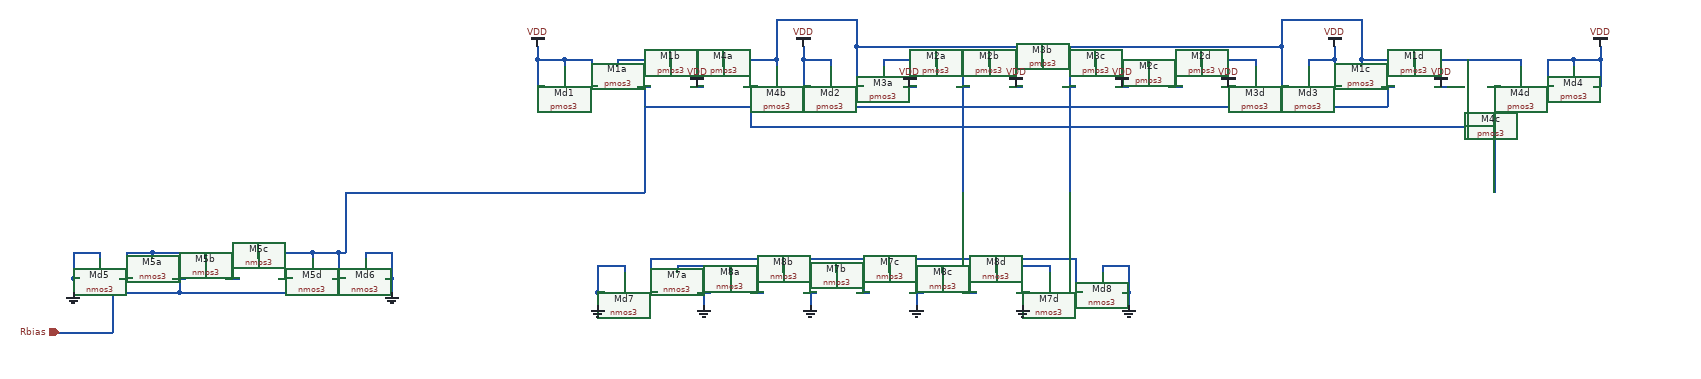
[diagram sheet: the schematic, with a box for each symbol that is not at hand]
v {xschem version=2.9.9 file_version=1.2 }
G {}
K {}
V {}
S {}
E {}
N 860 -950 880 -950 { lab=VDD}
N 940 -950 960 -950 { lab=#net1}
N 1020 -950 1040 -950 { lab=VDD}
N 1100 -950 1120 -950 { lab=#net2}
N 1180 -950 1200 -950 { lab=VDD}
N 1260 -950 1280 -950 { lab=#net3}
N 1340 -950 1360 -950 { lab=VDD}
N 1420 -950 1440 -950 { lab=#net4}
N 1500 -950 1520 -950 { lab=VDD}
N 1580 -950 1600 -950 { lab=#net3}
N 1660 -950 1680 -950 { lab=VDD}
N 1740 -950 1760 -950 { lab=#net4}
N 1820 -950 1840 -950 { lab=VDD}
N 1900 -950 1920 -950 { lab=#net3}
N 1980 -950 2000 -950 { lab=VDD}
N 2060 -950 2080 -950 { lab=#net1}
N 2140 -950 2160 -950 { lab=VDD}
N 2220 -950 2240 -950 { lab=#net2}
N 2300 -950 2320 -950 { lab=VDD}
N 790 -950 800 -950 { lab=VDD}
N 790 -990 790 -950 { lab=VDD}
N 790 -990 830 -990 { lab=VDD}
N 830 -990 830 -980 { lab=VDD}
N 790 -1010 790 -990 { lab=VDD}
N 2380 -950 2390 -950 { lab=VDD}
N 2350 -990 2350 -980 { lab=VDD}
N 2350 -990 2390 -990 { lab=VDD}
N 2390 -990 2390 -950 { lab=VDD}
N 2390 -1010 2390 -990 { lab=VDD}
N 1310 -990 1310 -980 { lab=#net4}
N 1310 -990 1870 -990 { lab=#net4}
N 1870 -990 1870 -980 { lab=#net4}
N 1790 -990 1790 -980 { lab=#net4}
N 1710 -990 1710 -980 { lab=#net4}
N 1630 -990 1630 -980 { lab=#net4}
N 1550 -990 1550 -980 { lab=#net4}
N 1470 -990 1470 -980 { lab=#net4}
N 1390 -990 1390 -980 { lab=#net4}
N 1430 -990 1430 -950 { lab=#net4}
N 1750 -990 1750 -950 { lab=#net4}
N 1910 -1010 1910 -950 { lab=#net3}
N 1270 -1010 1910 -1010 { lab=#net3}
N 1270 -1010 1270 -950 { lab=#net3}
N 1590 -1010 1590 -950 { lab=#net3}
N 1590 -950 1590 -790 { lab=#net3}
N 1430 -950 1430 -790 { lab=#net4}
N 1950 -990 1950 -980 { lab=VDD}
N 1950 -990 1990 -990 { lab=VDD}
N 1990 -990 1990 -950 { lab=VDD}
N 1990 -1010 1990 -990 { lab=VDD}
N 2270 -990 2270 -980 { lab=#net3}
N 2190 -990 2190 -980 { lab=#net3}
N 2110 -990 2110 -980 { lab=#net3}
N 2030 -990 2030 -980 { lab=#net3}
N 2030 -990 2270 -990 { lab=#net3}
N 1230 -990 1230 -980 { lab=VDD}
N 1190 -990 1230 -990 { lab=VDD}
N 1190 -990 1190 -950 { lab=VDD}
N 1190 -1010 1190 -990 { lab=VDD}
N 910 -990 910 -980 { lab=#net3}
N 910 -990 1150 -990 { lab=#net3}
N 1150 -990 1150 -980 { lab=#net3}
N 1070 -990 1070 -980 { lab=#net3}
N 990 -990 990 -980 { lab=#net3}
N 1150 -1050 1150 -990 { lab=#net3}
N 1150 -1050 1270 -1050 { lab=#net3}
N 1270 -1050 1270 -1010 { lab=#net3}
N 2030 -1050 2030 -990 { lab=#net3}
N 1910 -1050 2030 -1050 { lab=#net3}
N 1910 -1050 1910 -1010 { lab=#net3}
N 2230 -950 2230 -840 { lab=#net2}
N 2310 -990 2310 -950 { lab=VDD}
N 2310 -990 2350 -990 { lab=VDD}
N 870 -990 870 -950 { lab=VDD}
N 830 -990 870 -990 { lab=VDD}
N 950 -950 950 -790 { lab=#net1}
N 2230 -840 2230 -790 { lab=#net2}
N 2070 -950 2070 -920 { lab=#net1}
N 950 -920 2070 -920 { lab=#net1}
N 1110 -950 1110 -890 { lab=#net2}
N 1110 -890 2230 -890 { lab=#net2}
N 400 -660 420 -660 { lab=Rbias}
N 320 -660 340 -660 { lab=#net1}
N 240 -660 260 -660 { lab=Rbias}
N 450 -700 450 -690 { lab=#net1}
N 210 -700 450 -700 { lab=#net1}
N 210 -700 210 -690 { lab=#net1}
N 290 -700 290 -690 { lab=#net1}
N 370 -700 370 -690 { lab=#net1}
N 410 -660 410 -640 { lab=Rbias}
N 250 -640 410 -640 { lab=Rbias}
N 250 -660 250 -640 { lab=Rbias}
N 150 -640 250 -640 { lab=Rbias}
N 170 -660 180 -660 { lab=#net1}
N 480 -660 490 -660 { lab=#net1}
N 170 -700 210 -700 { lab=#net1}
N 170 -700 170 -660 { lab=#net1}
N 450 -700 490 -700 { lab=#net1}
N 490 -700 490 -660 { lab=#net1}
N 330 -700 330 -660 { lab=#net1}
N 500 -790 950 -790 { lab=#net1}
N 500 -790 500 -700 { lab=#net1}
N 490 -700 500 -700 { lab=#net1}
N 490 -660 500 -660 { lab=#net1}
N 530 -700 530 -690 { lab=GND}
N 530 -700 570 -700 { lab=GND}
N 570 -700 570 -660 { lab=GND}
N 560 -660 570 -660 { lab=GND}
N 570 -660 570 -640 { lab=GND}
N 160 -660 170 -660 { lab=#net1}
N 130 -700 130 -690 { lab=GND}
N 100 -700 130 -700 { lab=GND}
N 90 -660 100 -660 { lab=GND}
N 90 -700 100 -700 { lab=GND}
N 90 -700 90 -660 { lab=GND}
N 90 -660 90 -640 { lab=GND}
N 150 -640 150 -580 { lab=Rbias}
N 70 -580 150 -580 { lab=Rbias}
N 920 -680 920 -670 { lab=GND}
N 1000 -680 1000 -670 { lab=#net5}
N 1080 -680 1080 -670 { lab=#net5}
N 1160 -680 1160 -670 { lab=#net5}
N 950 -640 970 -640 { lab=#net5}
N 1030 -640 1050 -640 { lab=GND}
N 1110 -640 1130 -640 { lab=#net6}
N 1190 -640 1210 -640 { lab=#net7}
N 1240 -680 1240 -670 { lab=#net5}
N 1320 -680 1320 -670 { lab=#net5}
N 1400 -680 1400 -670 { lab=#net5}
N 1480 -680 1480 -670 { lab=#net5}
N 1270 -640 1290 -640 { lab=#net5}
N 1350 -640 1370 -640 { lab=#net8}
N 1430 -640 1450 -640 { lab=#net9}
N 1510 -640 1530 -640 { lab=#net10}
N 1560 -680 1560 -670 { lab=#net5}
N 1640 -680 1640 -670 { lab=GND}
N 1590 -640 1610 -640 { lab=#net5}
N 1000 -680 1560 -680 { lab=#net5}
N 880 -680 920 -680 { lab=GND}
N 880 -680 880 -640 { lab=GND}
N 880 -640 890 -640 { lab=GND}
N 1670 -640 1680 -640 { lab=GND}
N 1680 -680 1680 -640 { lab=GND}
N 1640 -680 1680 -680 { lab=GND}
N 1680 -640 1680 -620 { lab=GND}
N 880 -640 880 -620 { lab=GND}
N 1040 -640 1040 -620 { lab=GND}
N 1200 -640 1200 -620 { lab=GND}
N 1360 -640 1360 -620 { lab=GND}
N 1520 -640 1520 -620 { lab=GND}
N 1120 -680 1120 -640 {}
N 1440 -680 1440 -640 {}
N 960 -690 960 -640 {}
N 960 -690 1600 -690 {}
N 1600 -690 1600 -640 {}
N 1280 -690 1280 -640 {}
C {madvlsi/pmos3.sym} 830 -950 1 0 {name=Md1
L=0.5
W=1.4/4
body=VDD
nf=1
mult=1
ad="'int((nf+1)/2) * W/nf * 0.29'" 
pd="'2*int((nf+1)/2) * (W/nf + 0.29)'"
as="'int((nf+2)/2) * W/nf * 0.29'" 
ps="'2*int((nf+2)/2) * (W/nf + 0.29)'"
nrd="'0.29 / W'" nrs="'0.29 / W'"
sa=0 sb=0 sd=0
model=pfet_01v8
spiceprefix=X
}
C {madvlsi/pmos3.sym} 910 -950 1 0 {name=M1a
L=0.5
W=1.4/4
body=VDD
nf=1
mult=1
ad="'int((nf+1)/2) * W/nf * 0.29'" 
pd="'2*int((nf+1)/2) * (W/nf + 0.29)'"
as="'int((nf+2)/2) * W/nf * 0.29'" 
ps="'2*int((nf+2)/2) * (W/nf + 0.29)'"
nrd="'0.29 / W'" nrs="'0.29 / W'"
sa=0 sb=0 sd=0
model=pfet_01v8
spiceprefix=X
}
C {madvlsi/pmos3.sym} 990 -950 1 0 {name=M1b
L=0.5
W=1.4/4
body=VDD
nf=1
mult=1
ad="'int((nf+1)/2) * W/nf * 0.29'" 
pd="'2*int((nf+1)/2) * (W/nf + 0.29)'"
as="'int((nf+2)/2) * W/nf * 0.29'" 
ps="'2*int((nf+2)/2) * (W/nf + 0.29)'"
nrd="'0.29 / W'" nrs="'0.29 / W'"
sa=0 sb=0 sd=0
model=pfet_01v8
spiceprefix=X
}
C {madvlsi/pmos3.sym} 1070 -950 1 0 {name=M4a
L=0.5
W=1.4/4
body=VDD
nf=1
mult=1
ad="'int((nf+1)/2) * W/nf * 0.29'" 
pd="'2*int((nf+1)/2) * (W/nf + 0.29)'"
as="'int((nf+2)/2) * W/nf * 0.29'" 
ps="'2*int((nf+2)/2) * (W/nf + 0.29)'"
nrd="'0.29 / W'" nrs="'0.29 / W'"
sa=0 sb=0 sd=0
model=pfet_01v8
spiceprefix=X
}
C {madvlsi/pmos3.sym} 1150 -950 1 0 {name=M4b
L=0.5
W=1.4/4
body=VDD
nf=1
mult=1
ad="'int((nf+1)/2) * W/nf * 0.29'" 
pd="'2*int((nf+1)/2) * (W/nf + 0.29)'"
as="'int((nf+2)/2) * W/nf * 0.29'" 
ps="'2*int((nf+2)/2) * (W/nf + 0.29)'"
nrd="'0.29 / W'" nrs="'0.29 / W'"
sa=0 sb=0 sd=0
model=pfet_01v8
spiceprefix=X
}
C {madvlsi/pmos3.sym} 1230 -950 1 0 {name=Md2
L=0.5
W=1.4/4
body=VDD
nf=1
mult=1
ad="'int((nf+1)/2) * W/nf * 0.29'" 
pd="'2*int((nf+1)/2) * (W/nf + 0.29)'"
as="'int((nf+2)/2) * W/nf * 0.29'" 
ps="'2*int((nf+2)/2) * (W/nf + 0.29)'"
nrd="'0.29 / W'" nrs="'0.29 / W'"
sa=0 sb=0 sd=0
model=pfet_01v8
spiceprefix=X
}
C {madvlsi/pmos3.sym} 1310 -950 1 0 {name=M3a
L=0.5
W=1.4/4
body=VDD
nf=1
mult=1
ad="'int((nf+1)/2) * W/nf * 0.29'" 
pd="'2*int((nf+1)/2) * (W/nf + 0.29)'"
as="'int((nf+2)/2) * W/nf * 0.29'" 
ps="'2*int((nf+2)/2) * (W/nf + 0.29)'"
nrd="'0.29 / W'" nrs="'0.29 / W'"
sa=0 sb=0 sd=0
model=pfet_01v8
spiceprefix=X
}
C {madvlsi/pmos3.sym} 1390 -950 1 0 {name=M2a
L=0.5
W=1.4/4
body=VDD
nf=1
mult=1
ad="'int((nf+1)/2) * W/nf * 0.29'" 
pd="'2*int((nf+1)/2) * (W/nf + 0.29)'"
as="'int((nf+2)/2) * W/nf * 0.29'" 
ps="'2*int((nf+2)/2) * (W/nf + 0.29)'"
nrd="'0.29 / W'" nrs="'0.29 / W'"
sa=0 sb=0 sd=0
model=pfet_01v8
spiceprefix=X
}
C {madvlsi/pmos3.sym} 1470 -950 1 0 {name=M2b
L=0.5
W=1.4/4
body=VDD
nf=1
mult=1
ad="'int((nf+1)/2) * W/nf * 0.29'" 
pd="'2*int((nf+1)/2) * (W/nf + 0.29)'"
as="'int((nf+2)/2) * W/nf * 0.29'" 
ps="'2*int((nf+2)/2) * (W/nf + 0.29)'"
nrd="'0.29 / W'" nrs="'0.29 / W'"
sa=0 sb=0 sd=0
model=pfet_01v8
spiceprefix=X
}
C {madvlsi/pmos3.sym} 1550 -950 1 0 {name=M3b
L=0.5
W=1.4/4
body=VDD
nf=1
mult=1
ad="'int((nf+1)/2) * W/nf * 0.29'" 
pd="'2*int((nf+1)/2) * (W/nf + 0.29)'"
as="'int((nf+2)/2) * W/nf * 0.29'" 
ps="'2*int((nf+2)/2) * (W/nf + 0.29)'"
nrd="'0.29 / W'" nrs="'0.29 / W'"
sa=0 sb=0 sd=0
model=pfet_01v8
spiceprefix=X
}
C {madvlsi/pmos3.sym} 1630 -950 1 0 {name=M3c
L=0.5
W=1.4/4
body=VDD
nf=1
mult=1
ad="'int((nf+1)/2) * W/nf * 0.29'" 
pd="'2*int((nf+1)/2) * (W/nf + 0.29)'"
as="'int((nf+2)/2) * W/nf * 0.29'" 
ps="'2*int((nf+2)/2) * (W/nf + 0.29)'"
nrd="'0.29 / W'" nrs="'0.29 / W'"
sa=0 sb=0 sd=0
model=pfet_01v8
spiceprefix=X
}
C {madvlsi/pmos3.sym} 1710 -950 1 0 {name=M2c
L=0.5
W=1.4/4
body=VDD
nf=1
mult=1
ad="'int((nf+1)/2) * W/nf * 0.29'" 
pd="'2*int((nf+1)/2) * (W/nf + 0.29)'"
as="'int((nf+2)/2) * W/nf * 0.29'" 
ps="'2*int((nf+2)/2) * (W/nf + 0.29)'"
nrd="'0.29 / W'" nrs="'0.29 / W'"
sa=0 sb=0 sd=0
model=pfet_01v8
spiceprefix=X
}
C {madvlsi/pmos3.sym} 1790 -950 1 0 {name=M2d
L=0.5
W=1.4/4
body=VDD
nf=1
mult=1
ad="'int((nf+1)/2) * W/nf * 0.29'" 
pd="'2*int((nf+1)/2) * (W/nf + 0.29)'"
as="'int((nf+2)/2) * W/nf * 0.29'" 
ps="'2*int((nf+2)/2) * (W/nf + 0.29)'"
nrd="'0.29 / W'" nrs="'0.29 / W'"
sa=0 sb=0 sd=0
model=pfet_01v8
spiceprefix=X
}
C {madvlsi/pmos3.sym} 1870 -950 1 0 {name=M3d
L=0.5
W=1.4/4
body=VDD
nf=1
mult=1
ad="'int((nf+1)/2) * W/nf * 0.29'" 
pd="'2*int((nf+1)/2) * (W/nf + 0.29)'"
as="'int((nf+2)/2) * W/nf * 0.29'" 
ps="'2*int((nf+2)/2) * (W/nf + 0.29)'"
nrd="'0.29 / W'" nrs="'0.29 / W'"
sa=0 sb=0 sd=0
model=pfet_01v8
spiceprefix=X
}
C {madvlsi/pmos3.sym} 1950 -950 1 0 {name=Md3
L=0.5
W=1.4/4
body=VDD
nf=1
mult=1
ad="'int((nf+1)/2) * W/nf * 0.29'" 
pd="'2*int((nf+1)/2) * (W/nf + 0.29)'"
as="'int((nf+2)/2) * W/nf * 0.29'" 
ps="'2*int((nf+2)/2) * (W/nf + 0.29)'"
nrd="'0.29 / W'" nrs="'0.29 / W'"
sa=0 sb=0 sd=0
model=pfet_01v8
spiceprefix=X
}
C {madvlsi/pmos3.sym} 2030 -950 1 0 {name=M1c
L=0.5
W=1.4/4
body=VDD
nf=1
mult=1
ad="'int((nf+1)/2) * W/nf * 0.29'" 
pd="'2*int((nf+1)/2) * (W/nf + 0.29)'"
as="'int((nf+2)/2) * W/nf * 0.29'" 
ps="'2*int((nf+2)/2) * (W/nf + 0.29)'"
nrd="'0.29 / W'" nrs="'0.29 / W'"
sa=0 sb=0 sd=0
model=pfet_01v8
spiceprefix=X
}
C {madvlsi/pmos3.sym} 2110 -950 1 0 {name=M1d
L=0.5
W=1.4/4
body=VDD
nf=1
mult=1
ad="'int((nf+1)/2) * W/nf * 0.29'" 
pd="'2*int((nf+1)/2) * (W/nf + 0.29)'"
as="'int((nf+2)/2) * W/nf * 0.29'" 
ps="'2*int((nf+2)/2) * (W/nf + 0.29)'"
nrd="'0.29 / W'" nrs="'0.29 / W'"
sa=0 sb=0 sd=0
model=pfet_01v8
spiceprefix=X
}
C {madvlsi/pmos3.sym} 2190 -950 1 0 {name=M4c
L=0.5
W=1.4/4
body=VDD
nf=1
mult=1
ad="'int((nf+1)/2) * W/nf * 0.29'" 
pd="'2*int((nf+1)/2) * (W/nf + 0.29)'"
as="'int((nf+2)/2) * W/nf * 0.29'" 
ps="'2*int((nf+2)/2) * (W/nf + 0.29)'"
nrd="'0.29 / W'" nrs="'0.29 / W'"
sa=0 sb=0 sd=0
model=pfet_01v8
spiceprefix=X
}
C {madvlsi/pmos3.sym} 2270 -950 1 0 {name=M4d
L=0.5
W=1.4/4
body=VDD
nf=1
mult=1
ad="'int((nf+1)/2) * W/nf * 0.29'" 
pd="'2*int((nf+1)/2) * (W/nf + 0.29)'"
as="'int((nf+2)/2) * W/nf * 0.29'" 
ps="'2*int((nf+2)/2) * (W/nf + 0.29)'"
nrd="'0.29 / W'" nrs="'0.29 / W'"
sa=0 sb=0 sd=0
model=pfet_01v8
spiceprefix=X
}
C {madvlsi/pmos3.sym} 2350 -950 1 0 {name=Md4
L=0.5
W=1.4/4
body=VDD
nf=1
mult=1
ad="'int((nf+1)/2) * W/nf * 0.29'" 
pd="'2*int((nf+1)/2) * (W/nf + 0.29)'"
as="'int((nf+2)/2) * W/nf * 0.29'" 
ps="'2*int((nf+2)/2) * (W/nf + 0.29)'"
nrd="'0.29 / W'" nrs="'0.29 / W'"
sa=0 sb=0 sd=0
model=pfet_01v8
spiceprefix=X
}
C {madvlsi/vdd.sym} 1350 -950 0 0 {name=l1 lab=VDD}
C {madvlsi/vdd.sym} 1510 -950 0 0 {name=l2 lab=VDD}
C {madvlsi/vdd.sym} 1670 -950 0 0 {name=l3 lab=VDD}
C {madvlsi/vdd.sym} 1830 -950 0 0 {name=l4 lab=VDD}
C {madvlsi/vdd.sym} 1990 -1010 0 0 {name=l5 lab=VDD}
C {madvlsi/vdd.sym} 2390 -1010 0 0 {name=l6 lab=VDD}
C {madvlsi/vdd.sym} 1190 -1010 0 0 {name=l7 lab=VDD}
C {madvlsi/vdd.sym} 790 -1010 0 0 {name=l8 lab=VDD}
C {madvlsi/vdd.sym} 1030 -950 0 0 {name=l9 lab=VDD}
C {madvlsi/vdd.sym} 2150 -950 0 0 {name=l10 lab=VDD}
C {madvlsi/nmos3.sym} 210 -660 1 0 {name=M5a
L=0.5
W=1.4*2
body=GND
nf=1
mult=1
ad="'int((nf+1)/2) * W/nf * 0.29'" 
pd="'2*int((nf+1)/2) * (W/nf + 0.29)'"
as="'int((nf+2)/2) * W/nf * 0.29'" 
ps="'2*int((nf+2)/2) * (W/nf + 0.29)'"
nrd="'0.29 / W'" nrs="'0.29 / W'"
sa=0 sb=0 sd=0
model=nfet_01v8
spiceprefix=X
}
C {madvlsi/nmos3.sym} 290 -660 1 0 {name=M5b
L=0.5
W=1.4*2
body=GND
nf=1
mult=1
ad="'int((nf+1)/2) * W/nf * 0.29'" 
pd="'2*int((nf+1)/2) * (W/nf + 0.29)'"
as="'int((nf+2)/2) * W/nf * 0.29'" 
ps="'2*int((nf+2)/2) * (W/nf + 0.29)'"
nrd="'0.29 / W'" nrs="'0.29 / W'"
sa=0 sb=0 sd=0
model=nfet_01v8
spiceprefix=X
}
C {madvlsi/nmos3.sym} 370 -660 1 0 {name=M5c
L=0.5
W=1.4*2
body=GND
nf=1
mult=1
ad="'int((nf+1)/2) * W/nf * 0.29'" 
pd="'2*int((nf+1)/2) * (W/nf + 0.29)'"
as="'int((nf+2)/2) * W/nf * 0.29'" 
ps="'2*int((nf+2)/2) * (W/nf + 0.29)'"
nrd="'0.29 / W'" nrs="'0.29 / W'"
sa=0 sb=0 sd=0
model=nfet_01v8
spiceprefix=X
}
C {madvlsi/nmos3.sym} 450 -660 1 0 {name=M5d
L=0.5
W=1.4*2
body=GND
nf=1
mult=1
ad="'int((nf+1)/2) * W/nf * 0.29'" 
pd="'2*int((nf+1)/2) * (W/nf + 0.29)'"
as="'int((nf+2)/2) * W/nf * 0.29'" 
ps="'2*int((nf+2)/2) * (W/nf + 0.29)'"
nrd="'0.29 / W'" nrs="'0.29 / W'"
sa=0 sb=0 sd=0
model=nfet_01v8
spiceprefix=X
}
C {madvlsi/nmos3.sym} 530 -660 1 0 {name=Md6
L=0.5
W=1.4*2
body=GND
nf=1
mult=1
ad="'int((nf+1)/2) * W/nf * 0.29'" 
pd="'2*int((nf+1)/2) * (W/nf + 0.29)'"
as="'int((nf+2)/2) * W/nf * 0.29'" 
ps="'2*int((nf+2)/2) * (W/nf + 0.29)'"
nrd="'0.29 / W'" nrs="'0.29 / W'"
sa=0 sb=0 sd=0
model=nfet_01v8
spiceprefix=X
}
C {madvlsi/nmos3.sym} 130 -660 1 0 {name=Md5
L=0.5
W=1.4*2
body=GND
nf=1
mult=1
ad="'int((nf+1)/2) * W/nf * 0.29'" 
pd="'2*int((nf+1)/2) * (W/nf + 0.29)'"
as="'int((nf+2)/2) * W/nf * 0.29'" 
ps="'2*int((nf+2)/2) * (W/nf + 0.29)'"
nrd="'0.29 / W'" nrs="'0.29 / W'"
sa=0 sb=0 sd=0
model=nfet_01v8
spiceprefix=X
}
C {madvlsi/gnd.sym} 90 -640 0 0 {name=l11 lab=GND}
C {madvlsi/gnd.sym} 570 -640 0 0 {name=l12 lab=GND}
C {devices/iopin.sym} 70 -580 2 0 {name=p1 lab=Rbias}
C {madvlsi/nmos3.sym} 920 -640 1 0 {name=Md7
L=0.5
W=1.4/4
body=GND
nf=1
mult=1
ad="'int((nf+1)/2) * W/nf * 0.29'" 
pd="'2*int((nf+1)/2) * (W/nf + 0.29)'"
as="'int((nf+2)/2) * W/nf * 0.29'" 
ps="'2*int((nf+2)/2) * (W/nf + 0.29)'"
nrd="'0.29 / W'" nrs="'0.29 / W'"
sa=0 sb=0 sd=0
model=nfet_01v8
spiceprefix=X
}
C {madvlsi/nmos3.sym} 1000 -640 1 0 {name=M7a
L=0.5
W=1.4/4
body=GND
nf=1
mult=1
ad="'int((nf+1)/2) * W/nf * 0.29'" 
pd="'2*int((nf+1)/2) * (W/nf + 0.29)'"
as="'int((nf+2)/2) * W/nf * 0.29'" 
ps="'2*int((nf+2)/2) * (W/nf + 0.29)'"
nrd="'0.29 / W'" nrs="'0.29 / W'"
sa=0 sb=0 sd=0
model=nfet_01v8
spiceprefix=X
}
C {madvlsi/nmos3.sym} 1080 -640 1 0 {name=M8a
L=0.5
W=1.4/4
body=GND
nf=1
mult=1
ad="'int((nf+1)/2) * W/nf * 0.29'" 
pd="'2*int((nf+1)/2) * (W/nf + 0.29)'"
as="'int((nf+2)/2) * W/nf * 0.29'" 
ps="'2*int((nf+2)/2) * (W/nf + 0.29)'"
nrd="'0.29 / W'" nrs="'0.29 / W'"
sa=0 sb=0 sd=0
model=nfet_01v8
spiceprefix=X
}
C {madvlsi/nmos3.sym} 1160 -640 1 0 {name=M8b
L=0.5
W=1.4/4
body=GND
nf=1
mult=1
ad="'int((nf+1)/2) * W/nf * 0.29'" 
pd="'2*int((nf+1)/2) * (W/nf + 0.29)'"
as="'int((nf+2)/2) * W/nf * 0.29'" 
ps="'2*int((nf+2)/2) * (W/nf + 0.29)'"
nrd="'0.29 / W'" nrs="'0.29 / W'"
sa=0 sb=0 sd=0
model=nfet_01v8
spiceprefix=X
}
C {madvlsi/nmos3.sym} 1240 -640 1 0 {name=M7b
L=0.5
W=1.4/4
body=GND
nf=1
mult=1
ad="'int((nf+1)/2) * W/nf * 0.29'" 
pd="'2*int((nf+1)/2) * (W/nf + 0.29)'"
as="'int((nf+2)/2) * W/nf * 0.29'" 
ps="'2*int((nf+2)/2) * (W/nf + 0.29)'"
nrd="'0.29 / W'" nrs="'0.29 / W'"
sa=0 sb=0 sd=0
model=nfet_01v8
spiceprefix=X
}
C {madvlsi/nmos3.sym} 1320 -640 1 0 {name=M7c
L=0.5
W=1.4/4
body=GND
nf=1
mult=1
ad="'int((nf+1)/2) * W/nf * 0.29'" 
pd="'2*int((nf+1)/2) * (W/nf + 0.29)'"
as="'int((nf+2)/2) * W/nf * 0.29'" 
ps="'2*int((nf+2)/2) * (W/nf + 0.29)'"
nrd="'0.29 / W'" nrs="'0.29 / W'"
sa=0 sb=0 sd=0
model=nfet_01v8
spiceprefix=X
}
C {madvlsi/nmos3.sym} 1400 -640 1 0 {name=M8c
L=0.5
W=1.4/4
body=GND
nf=1
mult=1
ad="'int((nf+1)/2) * W/nf * 0.29'" 
pd="'2*int((nf+1)/2) * (W/nf + 0.29)'"
as="'int((nf+2)/2) * W/nf * 0.29'" 
ps="'2*int((nf+2)/2) * (W/nf + 0.29)'"
nrd="'0.29 / W'" nrs="'0.29 / W'"
sa=0 sb=0 sd=0
model=nfet_01v8
spiceprefix=X
}
C {madvlsi/nmos3.sym} 1480 -640 1 0 {name=M8d
L=0.5
W=1.4/4
body=GND
nf=1
mult=1
ad="'int((nf+1)/2) * W/nf * 0.29'" 
pd="'2*int((nf+1)/2) * (W/nf + 0.29)'"
as="'int((nf+2)/2) * W/nf * 0.29'" 
ps="'2*int((nf+2)/2) * (W/nf + 0.29)'"
nrd="'0.29 / W'" nrs="'0.29 / W'"
sa=0 sb=0 sd=0
model=nfet_01v8
spiceprefix=X
}
C {madvlsi/nmos3.sym} 1560 -640 1 0 {name=M7d
L=0.5
W=1.4/4
body=GND
nf=1
mult=1
ad="'int((nf+1)/2) * W/nf * 0.29'" 
pd="'2*int((nf+1)/2) * (W/nf + 0.29)'"
as="'int((nf+2)/2) * W/nf * 0.29'" 
ps="'2*int((nf+2)/2) * (W/nf + 0.29)'"
nrd="'0.29 / W'" nrs="'0.29 / W'"
sa=0 sb=0 sd=0
model=nfet_01v8
spiceprefix=X
}
C {madvlsi/nmos3.sym} 1640 -640 1 0 {name=Md8
L=0.5
W=1.4/4
body=GND
nf=1
mult=1
ad="'int((nf+1)/2) * W/nf * 0.29'" 
pd="'2*int((nf+1)/2) * (W/nf + 0.29)'"
as="'int((nf+2)/2) * W/nf * 0.29'" 
ps="'2*int((nf+2)/2) * (W/nf + 0.29)'"
nrd="'0.29 / W'" nrs="'0.29 / W'"
sa=0 sb=0 sd=0
model=nfet_01v8
spiceprefix=X
}
C {madvlsi/gnd.sym} 880 -620 0 0 {name=l13 lab=GND}
C {madvlsi/gnd.sym} 1680 -620 0 0 {name=l14 lab=GND}
C {madvlsi/gnd.sym} 1040 -620 0 0 {name=l15 lab=GND}
C {madvlsi/gnd.sym} 1200 -620 0 0 {name=l16 lab=GND}
C {madvlsi/gnd.sym} 1360 -620 0 0 {name=l17 lab=GND}
C {madvlsi/gnd.sym} 1520 -620 0 0 {name=l18 lab=GND}
